VERSION 5.7 ;
BUSBITCHARS "[]" ;
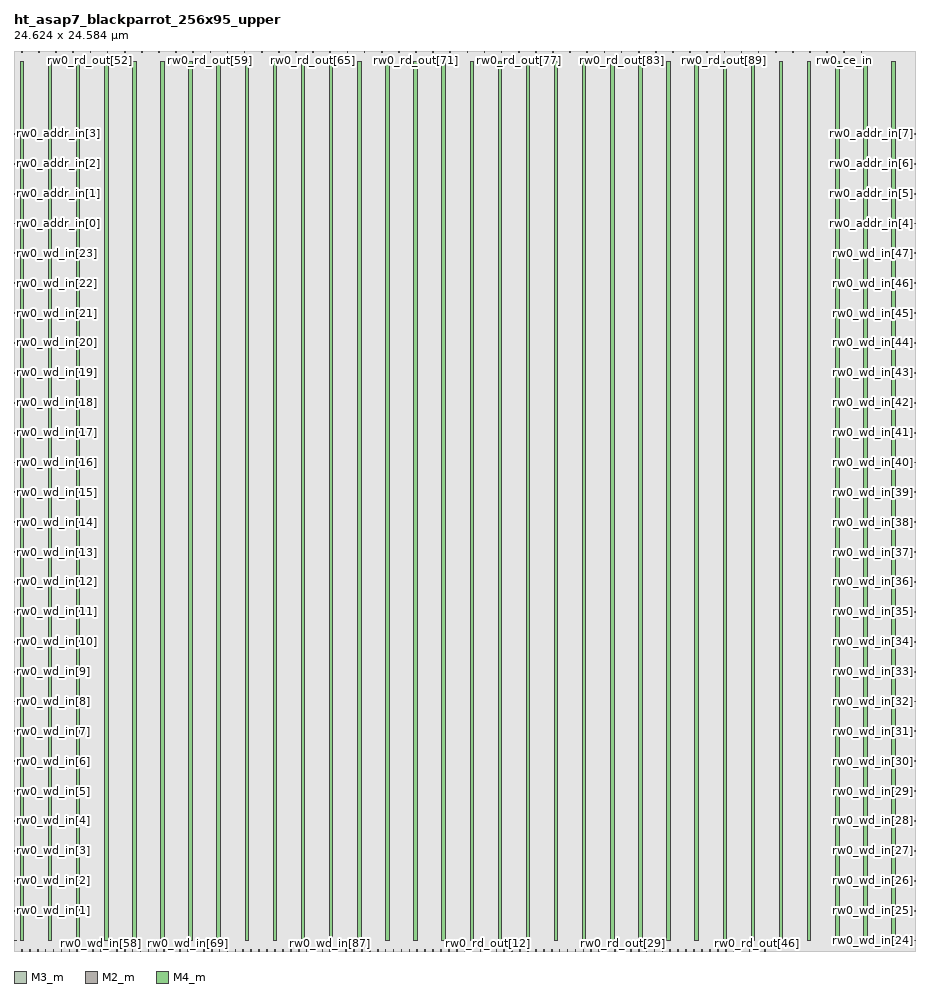
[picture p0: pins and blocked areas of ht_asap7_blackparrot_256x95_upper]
MACRO ht_asap7_blackparrot_256x95_upper
  FOREIGN ht_asap7_blackparrot_256x95_upper 0 0 ;
  SYMMETRY X Y R90 ;
  SIZE 24.624 BY 24.584 ;
  CLASS COVER ;
  PIN rw0_wd_in[0]
    DIRECTION INPUT ;
    USE SIGNAL ;
    SHAPE ABUTMENT ;
    PORT
      LAYER M3_m ;
      RECT 0.000 0.276 0.072 0.300 ;
    END
  END rw0_wd_in[0]
  PIN rw0_wd_in[1]
    DIRECTION INPUT ;
    USE SIGNAL ;
    SHAPE ABUTMENT ;
    PORT
      LAYER M3_m ;
      RECT 0.000 1.092 0.072 1.116 ;
    END
  END rw0_wd_in[1]
  PIN rw0_wd_in[2]
    DIRECTION INPUT ;
    USE SIGNAL ;
    SHAPE ABUTMENT ;
    PORT
      LAYER M3_m ;
      RECT 0.000 1.908 0.072 1.932 ;
    END
  END rw0_wd_in[2]
  PIN rw0_wd_in[3]
    DIRECTION INPUT ;
    USE SIGNAL ;
    SHAPE ABUTMENT ;
    PORT
      LAYER M3_m ;
      RECT 0.000 2.724 0.072 2.748 ;
    END
  END rw0_wd_in[3]
  PIN rw0_wd_in[4]
    DIRECTION INPUT ;
    USE SIGNAL ;
    SHAPE ABUTMENT ;
    PORT
      LAYER M3_m ;
      RECT 0.000 3.540 0.072 3.564 ;
    END
  END rw0_wd_in[4]
  PIN rw0_wd_in[5]
    DIRECTION INPUT ;
    USE SIGNAL ;
    SHAPE ABUTMENT ;
    PORT
      LAYER M3_m ;
      RECT 0.000 4.356 0.072 4.380 ;
    END
  END rw0_wd_in[5]
  PIN rw0_wd_in[6]
    DIRECTION INPUT ;
    USE SIGNAL ;
    SHAPE ABUTMENT ;
    PORT
      LAYER M3_m ;
      RECT 0.000 5.172 0.072 5.196 ;
    END
  END rw0_wd_in[6]
  PIN rw0_wd_in[7]
    DIRECTION INPUT ;
    USE SIGNAL ;
    SHAPE ABUTMENT ;
    PORT
      LAYER M3_m ;
      RECT 0.000 5.988 0.072 6.012 ;
    END
  END rw0_wd_in[7]
  PIN rw0_wd_in[8]
    DIRECTION INPUT ;
    USE SIGNAL ;
    SHAPE ABUTMENT ;
    PORT
      LAYER M3_m ;
      RECT 0.000 6.804 0.072 6.828 ;
    END
  END rw0_wd_in[8]
  PIN rw0_wd_in[9]
    DIRECTION INPUT ;
    USE SIGNAL ;
    SHAPE ABUTMENT ;
    PORT
      LAYER M3_m ;
      RECT 0.000 7.620 0.072 7.644 ;
    END
  END rw0_wd_in[9]
  PIN rw0_wd_in[10]
    DIRECTION INPUT ;
    USE SIGNAL ;
    SHAPE ABUTMENT ;
    PORT
      LAYER M3_m ;
      RECT 0.000 8.436 0.072 8.460 ;
    END
  END rw0_wd_in[10]
  PIN rw0_wd_in[11]
    DIRECTION INPUT ;
    USE SIGNAL ;
    SHAPE ABUTMENT ;
    PORT
      LAYER M3_m ;
      RECT 0.000 9.252 0.072 9.276 ;
    END
  END rw0_wd_in[11]
  PIN rw0_wd_in[12]
    DIRECTION INPUT ;
    USE SIGNAL ;
    SHAPE ABUTMENT ;
    PORT
      LAYER M3_m ;
      RECT 0.000 10.068 0.072 10.092 ;
    END
  END rw0_wd_in[12]
  PIN rw0_wd_in[13]
    DIRECTION INPUT ;
    USE SIGNAL ;
    SHAPE ABUTMENT ;
    PORT
      LAYER M3_m ;
      RECT 0.000 10.884 0.072 10.908 ;
    END
  END rw0_wd_in[13]
  PIN rw0_wd_in[14]
    DIRECTION INPUT ;
    USE SIGNAL ;
    SHAPE ABUTMENT ;
    PORT
      LAYER M3_m ;
      RECT 0.000 11.700 0.072 11.724 ;
    END
  END rw0_wd_in[14]
  PIN rw0_wd_in[15]
    DIRECTION INPUT ;
    USE SIGNAL ;
    SHAPE ABUTMENT ;
    PORT
      LAYER M3_m ;
      RECT 0.000 12.516 0.072 12.540 ;
    END
  END rw0_wd_in[15]
  PIN rw0_wd_in[16]
    DIRECTION INPUT ;
    USE SIGNAL ;
    SHAPE ABUTMENT ;
    PORT
      LAYER M3_m ;
      RECT 0.000 13.332 0.072 13.356 ;
    END
  END rw0_wd_in[16]
  PIN rw0_wd_in[17]
    DIRECTION INPUT ;
    USE SIGNAL ;
    SHAPE ABUTMENT ;
    PORT
      LAYER M3_m ;
      RECT 0.000 14.148 0.072 14.172 ;
    END
  END rw0_wd_in[17]
  PIN rw0_wd_in[18]
    DIRECTION INPUT ;
    USE SIGNAL ;
    SHAPE ABUTMENT ;
    PORT
      LAYER M3_m ;
      RECT 0.000 14.964 0.072 14.988 ;
    END
  END rw0_wd_in[18]
  PIN rw0_wd_in[19]
    DIRECTION INPUT ;
    USE SIGNAL ;
    SHAPE ABUTMENT ;
    PORT
      LAYER M3_m ;
      RECT 0.000 15.780 0.072 15.804 ;
    END
  END rw0_wd_in[19]
  PIN rw0_wd_in[20]
    DIRECTION INPUT ;
    USE SIGNAL ;
    SHAPE ABUTMENT ;
    PORT
      LAYER M3_m ;
      RECT 0.000 16.596 0.072 16.620 ;
    END
  END rw0_wd_in[20]
  PIN rw0_wd_in[21]
    DIRECTION INPUT ;
    USE SIGNAL ;
    SHAPE ABUTMENT ;
    PORT
      LAYER M3_m ;
      RECT 0.000 17.412 0.072 17.436 ;
    END
  END rw0_wd_in[21]
  PIN rw0_wd_in[22]
    DIRECTION INPUT ;
    USE SIGNAL ;
    SHAPE ABUTMENT ;
    PORT
      LAYER M3_m ;
      RECT 0.000 18.228 0.072 18.252 ;
    END
  END rw0_wd_in[22]
  PIN rw0_wd_in[23]
    DIRECTION INPUT ;
    USE SIGNAL ;
    SHAPE ABUTMENT ;
    PORT
      LAYER M3_m ;
      RECT 0.000 19.044 0.072 19.068 ;
    END
  END rw0_wd_in[23]
  PIN rw0_wd_in[24]
    DIRECTION INPUT ;
    USE SIGNAL ;
    SHAPE ABUTMENT ;
    PORT
      LAYER M3_m ;
      RECT 24.552 0.276 24.624 0.300 ;
    END
  END rw0_wd_in[24]
  PIN rw0_wd_in[25]
    DIRECTION INPUT ;
    USE SIGNAL ;
    SHAPE ABUTMENT ;
    PORT
      LAYER M3_m ;
      RECT 24.552 1.092 24.624 1.116 ;
    END
  END rw0_wd_in[25]
  PIN rw0_wd_in[26]
    DIRECTION INPUT ;
    USE SIGNAL ;
    SHAPE ABUTMENT ;
    PORT
      LAYER M3_m ;
      RECT 24.552 1.908 24.624 1.932 ;
    END
  END rw0_wd_in[26]
  PIN rw0_wd_in[27]
    DIRECTION INPUT ;
    USE SIGNAL ;
    SHAPE ABUTMENT ;
    PORT
      LAYER M3_m ;
      RECT 24.552 2.724 24.624 2.748 ;
    END
  END rw0_wd_in[27]
  PIN rw0_wd_in[28]
    DIRECTION INPUT ;
    USE SIGNAL ;
    SHAPE ABUTMENT ;
    PORT
      LAYER M3_m ;
      RECT 24.552 3.540 24.624 3.564 ;
    END
  END rw0_wd_in[28]
  PIN rw0_wd_in[29]
    DIRECTION INPUT ;
    USE SIGNAL ;
    SHAPE ABUTMENT ;
    PORT
      LAYER M3_m ;
      RECT 24.552 4.356 24.624 4.380 ;
    END
  END rw0_wd_in[29]
  PIN rw0_wd_in[30]
    DIRECTION INPUT ;
    USE SIGNAL ;
    SHAPE ABUTMENT ;
    PORT
      LAYER M3_m ;
      RECT 24.552 5.172 24.624 5.196 ;
    END
  END rw0_wd_in[30]
  PIN rw0_wd_in[31]
    DIRECTION INPUT ;
    USE SIGNAL ;
    SHAPE ABUTMENT ;
    PORT
      LAYER M3_m ;
      RECT 24.552 5.988 24.624 6.012 ;
    END
  END rw0_wd_in[31]
  PIN rw0_wd_in[32]
    DIRECTION INPUT ;
    USE SIGNAL ;
    SHAPE ABUTMENT ;
    PORT
      LAYER M3_m ;
      RECT 24.552 6.804 24.624 6.828 ;
    END
  END rw0_wd_in[32]
  PIN rw0_wd_in[33]
    DIRECTION INPUT ;
    USE SIGNAL ;
    SHAPE ABUTMENT ;
    PORT
      LAYER M3_m ;
      RECT 24.552 7.620 24.624 7.644 ;
    END
  END rw0_wd_in[33]
  PIN rw0_wd_in[34]
    DIRECTION INPUT ;
    USE SIGNAL ;
    SHAPE ABUTMENT ;
    PORT
      LAYER M3_m ;
      RECT 24.552 8.436 24.624 8.460 ;
    END
  END rw0_wd_in[34]
  PIN rw0_wd_in[35]
    DIRECTION INPUT ;
    USE SIGNAL ;
    SHAPE ABUTMENT ;
    PORT
      LAYER M3_m ;
      RECT 24.552 9.252 24.624 9.276 ;
    END
  END rw0_wd_in[35]
  PIN rw0_wd_in[36]
    DIRECTION INPUT ;
    USE SIGNAL ;
    SHAPE ABUTMENT ;
    PORT
      LAYER M3_m ;
      RECT 24.552 10.068 24.624 10.092 ;
    END
  END rw0_wd_in[36]
  PIN rw0_wd_in[37]
    DIRECTION INPUT ;
    USE SIGNAL ;
    SHAPE ABUTMENT ;
    PORT
      LAYER M3_m ;
      RECT 24.552 10.884 24.624 10.908 ;
    END
  END rw0_wd_in[37]
  PIN rw0_wd_in[38]
    DIRECTION INPUT ;
    USE SIGNAL ;
    SHAPE ABUTMENT ;
    PORT
      LAYER M3_m ;
      RECT 24.552 11.700 24.624 11.724 ;
    END
  END rw0_wd_in[38]
  PIN rw0_wd_in[39]
    DIRECTION INPUT ;
    USE SIGNAL ;
    SHAPE ABUTMENT ;
    PORT
      LAYER M3_m ;
      RECT 24.552 12.516 24.624 12.540 ;
    END
  END rw0_wd_in[39]
  PIN rw0_wd_in[40]
    DIRECTION INPUT ;
    USE SIGNAL ;
    SHAPE ABUTMENT ;
    PORT
      LAYER M3_m ;
      RECT 24.552 13.332 24.624 13.356 ;
    END
  END rw0_wd_in[40]
  PIN rw0_wd_in[41]
    DIRECTION INPUT ;
    USE SIGNAL ;
    SHAPE ABUTMENT ;
    PORT
      LAYER M3_m ;
      RECT 24.552 14.148 24.624 14.172 ;
    END
  END rw0_wd_in[41]
  PIN rw0_wd_in[42]
    DIRECTION INPUT ;
    USE SIGNAL ;
    SHAPE ABUTMENT ;
    PORT
      LAYER M3_m ;
      RECT 24.552 14.964 24.624 14.988 ;
    END
  END rw0_wd_in[42]
  PIN rw0_wd_in[43]
    DIRECTION INPUT ;
    USE SIGNAL ;
    SHAPE ABUTMENT ;
    PORT
      LAYER M3_m ;
      RECT 24.552 15.780 24.624 15.804 ;
    END
  END rw0_wd_in[43]
  PIN rw0_wd_in[44]
    DIRECTION INPUT ;
    USE SIGNAL ;
    SHAPE ABUTMENT ;
    PORT
      LAYER M3_m ;
      RECT 24.552 16.596 24.624 16.620 ;
    END
  END rw0_wd_in[44]
  PIN rw0_wd_in[45]
    DIRECTION INPUT ;
    USE SIGNAL ;
    SHAPE ABUTMENT ;
    PORT
      LAYER M3_m ;
      RECT 24.552 17.412 24.624 17.436 ;
    END
  END rw0_wd_in[45]
  PIN rw0_wd_in[46]
    DIRECTION INPUT ;
    USE SIGNAL ;
    SHAPE ABUTMENT ;
    PORT
      LAYER M3_m ;
      RECT 24.552 18.228 24.624 18.252 ;
    END
  END rw0_wd_in[46]
  PIN rw0_wd_in[47]
    DIRECTION INPUT ;
    USE SIGNAL ;
    SHAPE ABUTMENT ;
    PORT
      LAYER M3_m ;
      RECT 24.552 19.044 24.624 19.068 ;
    END
  END rw0_wd_in[47]
  PIN rw0_wd_in[48]
    DIRECTION INPUT ;
    USE SIGNAL ;
    SHAPE ABUTMENT ;
    PORT
      LAYER M2_m ;
      RECT 0.207 0.000 0.225 0.054 ;
    END
  END rw0_wd_in[48]
  PIN rw0_wd_in[49]
    DIRECTION INPUT ;
    USE SIGNAL ;
    SHAPE ABUTMENT ;
    PORT
      LAYER M2_m ;
      RECT 0.423 0.000 0.441 0.054 ;
    END
  END rw0_wd_in[49]
  PIN rw0_wd_in[50]
    DIRECTION INPUT ;
    USE SIGNAL ;
    SHAPE ABUTMENT ;
    PORT
      LAYER M2_m ;
      RECT 0.639 0.000 0.657 0.054 ;
    END
  END rw0_wd_in[50]
  PIN rw0_wd_in[51]
    DIRECTION INPUT ;
    USE SIGNAL ;
    SHAPE ABUTMENT ;
    PORT
      LAYER M2_m ;
      RECT 0.855 0.000 0.873 0.054 ;
    END
  END rw0_wd_in[51]
  PIN rw0_wd_in[52]
    DIRECTION INPUT ;
    USE SIGNAL ;
    SHAPE ABUTMENT ;
    PORT
      LAYER M2_m ;
      RECT 1.071 0.000 1.089 0.054 ;
    END
  END rw0_wd_in[52]
  PIN rw0_wd_in[53]
    DIRECTION INPUT ;
    USE SIGNAL ;
    SHAPE ABUTMENT ;
    PORT
      LAYER M2_m ;
      RECT 1.287 0.000 1.305 0.054 ;
    END
  END rw0_wd_in[53]
  PIN rw0_wd_in[54]
    DIRECTION INPUT ;
    USE SIGNAL ;
    SHAPE ABUTMENT ;
    PORT
      LAYER M2_m ;
      RECT 1.503 0.000 1.521 0.054 ;
    END
  END rw0_wd_in[54]
  PIN rw0_wd_in[55]
    DIRECTION INPUT ;
    USE SIGNAL ;
    SHAPE ABUTMENT ;
    PORT
      LAYER M2_m ;
      RECT 1.719 0.000 1.737 0.054 ;
    END
  END rw0_wd_in[55]
  PIN rw0_wd_in[56]
    DIRECTION INPUT ;
    USE SIGNAL ;
    SHAPE ABUTMENT ;
    PORT
      LAYER M2_m ;
      RECT 1.935 0.000 1.953 0.054 ;
    END
  END rw0_wd_in[56]
  PIN rw0_wd_in[57]
    DIRECTION INPUT ;
    USE SIGNAL ;
    SHAPE ABUTMENT ;
    PORT
      LAYER M2_m ;
      RECT 2.151 0.000 2.169 0.054 ;
    END
  END rw0_wd_in[57]
  PIN rw0_wd_in[58]
    DIRECTION INPUT ;
    USE SIGNAL ;
    SHAPE ABUTMENT ;
    PORT
      LAYER M2_m ;
      RECT 2.367 0.000 2.385 0.054 ;
    END
  END rw0_wd_in[58]
  PIN rw0_wd_in[59]
    DIRECTION INPUT ;
    USE SIGNAL ;
    SHAPE ABUTMENT ;
    PORT
      LAYER M2_m ;
      RECT 2.583 0.000 2.601 0.054 ;
    END
  END rw0_wd_in[59]
  PIN rw0_wd_in[60]
    DIRECTION INPUT ;
    USE SIGNAL ;
    SHAPE ABUTMENT ;
    PORT
      LAYER M2_m ;
      RECT 2.799 0.000 2.817 0.054 ;
    END
  END rw0_wd_in[60]
  PIN rw0_wd_in[61]
    DIRECTION INPUT ;
    USE SIGNAL ;
    SHAPE ABUTMENT ;
    PORT
      LAYER M2_m ;
      RECT 3.015 0.000 3.033 0.054 ;
    END
  END rw0_wd_in[61]
  PIN rw0_wd_in[62]
    DIRECTION INPUT ;
    USE SIGNAL ;
    SHAPE ABUTMENT ;
    PORT
      LAYER M2_m ;
      RECT 3.231 0.000 3.249 0.054 ;
    END
  END rw0_wd_in[62]
  PIN rw0_wd_in[63]
    DIRECTION INPUT ;
    USE SIGNAL ;
    SHAPE ABUTMENT ;
    PORT
      LAYER M2_m ;
      RECT 3.447 0.000 3.465 0.054 ;
    END
  END rw0_wd_in[63]
  PIN rw0_wd_in[64]
    DIRECTION INPUT ;
    USE SIGNAL ;
    SHAPE ABUTMENT ;
    PORT
      LAYER M2_m ;
      RECT 3.663 0.000 3.681 0.054 ;
    END
  END rw0_wd_in[64]
  PIN rw0_wd_in[65]
    DIRECTION INPUT ;
    USE SIGNAL ;
    SHAPE ABUTMENT ;
    PORT
      LAYER M2_m ;
      RECT 3.879 0.000 3.897 0.054 ;
    END
  END rw0_wd_in[65]
  PIN rw0_wd_in[66]
    DIRECTION INPUT ;
    USE SIGNAL ;
    SHAPE ABUTMENT ;
    PORT
      LAYER M2_m ;
      RECT 4.095 0.000 4.113 0.054 ;
    END
  END rw0_wd_in[66]
  PIN rw0_wd_in[67]
    DIRECTION INPUT ;
    USE SIGNAL ;
    SHAPE ABUTMENT ;
    PORT
      LAYER M2_m ;
      RECT 4.311 0.000 4.329 0.054 ;
    END
  END rw0_wd_in[67]
  PIN rw0_wd_in[68]
    DIRECTION INPUT ;
    USE SIGNAL ;
    SHAPE ABUTMENT ;
    PORT
      LAYER M2_m ;
      RECT 4.527 0.000 4.545 0.054 ;
    END
  END rw0_wd_in[68]
  PIN rw0_wd_in[69]
    DIRECTION INPUT ;
    USE SIGNAL ;
    SHAPE ABUTMENT ;
    PORT
      LAYER M2_m ;
      RECT 4.743 0.000 4.761 0.054 ;
    END
  END rw0_wd_in[69]
  PIN rw0_wd_in[70]
    DIRECTION INPUT ;
    USE SIGNAL ;
    SHAPE ABUTMENT ;
    PORT
      LAYER M2_m ;
      RECT 4.959 0.000 4.977 0.054 ;
    END
  END rw0_wd_in[70]
  PIN rw0_wd_in[71]
    DIRECTION INPUT ;
    USE SIGNAL ;
    SHAPE ABUTMENT ;
    PORT
      LAYER M2_m ;
      RECT 5.175 0.000 5.193 0.054 ;
    END
  END rw0_wd_in[71]
  PIN rw0_wd_in[72]
    DIRECTION INPUT ;
    USE SIGNAL ;
    SHAPE ABUTMENT ;
    PORT
      LAYER M2_m ;
      RECT 5.391 0.000 5.409 0.054 ;
    END
  END rw0_wd_in[72]
  PIN rw0_wd_in[73]
    DIRECTION INPUT ;
    USE SIGNAL ;
    SHAPE ABUTMENT ;
    PORT
      LAYER M2_m ;
      RECT 5.607 0.000 5.625 0.054 ;
    END
  END rw0_wd_in[73]
  PIN rw0_wd_in[74]
    DIRECTION INPUT ;
    USE SIGNAL ;
    SHAPE ABUTMENT ;
    PORT
      LAYER M2_m ;
      RECT 5.823 0.000 5.841 0.054 ;
    END
  END rw0_wd_in[74]
  PIN rw0_wd_in[75]
    DIRECTION INPUT ;
    USE SIGNAL ;
    SHAPE ABUTMENT ;
    PORT
      LAYER M2_m ;
      RECT 6.039 0.000 6.057 0.054 ;
    END
  END rw0_wd_in[75]
  PIN rw0_wd_in[76]
    DIRECTION INPUT ;
    USE SIGNAL ;
    SHAPE ABUTMENT ;
    PORT
      LAYER M2_m ;
      RECT 6.255 0.000 6.273 0.054 ;
    END
  END rw0_wd_in[76]
  PIN rw0_wd_in[77]
    DIRECTION INPUT ;
    USE SIGNAL ;
    SHAPE ABUTMENT ;
    PORT
      LAYER M2_m ;
      RECT 6.471 0.000 6.489 0.054 ;
    END
  END rw0_wd_in[77]
  PIN rw0_wd_in[78]
    DIRECTION INPUT ;
    USE SIGNAL ;
    SHAPE ABUTMENT ;
    PORT
      LAYER M2_m ;
      RECT 6.687 0.000 6.705 0.054 ;
    END
  END rw0_wd_in[78]
  PIN rw0_wd_in[79]
    DIRECTION INPUT ;
    USE SIGNAL ;
    SHAPE ABUTMENT ;
    PORT
      LAYER M2_m ;
      RECT 6.903 0.000 6.921 0.054 ;
    END
  END rw0_wd_in[79]
  PIN rw0_wd_in[80]
    DIRECTION INPUT ;
    USE SIGNAL ;
    SHAPE ABUTMENT ;
    PORT
      LAYER M2_m ;
      RECT 7.119 0.000 7.137 0.054 ;
    END
  END rw0_wd_in[80]
  PIN rw0_wd_in[81]
    DIRECTION INPUT ;
    USE SIGNAL ;
    SHAPE ABUTMENT ;
    PORT
      LAYER M2_m ;
      RECT 7.335 0.000 7.353 0.054 ;
    END
  END rw0_wd_in[81]
  PIN rw0_wd_in[82]
    DIRECTION INPUT ;
    USE SIGNAL ;
    SHAPE ABUTMENT ;
    PORT
      LAYER M2_m ;
      RECT 7.551 0.000 7.569 0.054 ;
    END
  END rw0_wd_in[82]
  PIN rw0_wd_in[83]
    DIRECTION INPUT ;
    USE SIGNAL ;
    SHAPE ABUTMENT ;
    PORT
      LAYER M2_m ;
      RECT 7.767 0.000 7.785 0.054 ;
    END
  END rw0_wd_in[83]
  PIN rw0_wd_in[84]
    DIRECTION INPUT ;
    USE SIGNAL ;
    SHAPE ABUTMENT ;
    PORT
      LAYER M2_m ;
      RECT 7.983 0.000 8.001 0.054 ;
    END
  END rw0_wd_in[84]
  PIN rw0_wd_in[85]
    DIRECTION INPUT ;
    USE SIGNAL ;
    SHAPE ABUTMENT ;
    PORT
      LAYER M2_m ;
      RECT 8.199 0.000 8.217 0.054 ;
    END
  END rw0_wd_in[85]
  PIN rw0_wd_in[86]
    DIRECTION INPUT ;
    USE SIGNAL ;
    SHAPE ABUTMENT ;
    PORT
      LAYER M2_m ;
      RECT 8.415 0.000 8.433 0.054 ;
    END
  END rw0_wd_in[86]
  PIN rw0_wd_in[87]
    DIRECTION INPUT ;
    USE SIGNAL ;
    SHAPE ABUTMENT ;
    PORT
      LAYER M2_m ;
      RECT 8.631 0.000 8.649 0.054 ;
    END
  END rw0_wd_in[87]
  PIN rw0_wd_in[88]
    DIRECTION INPUT ;
    USE SIGNAL ;
    SHAPE ABUTMENT ;
    PORT
      LAYER M2_m ;
      RECT 8.847 0.000 8.865 0.054 ;
    END
  END rw0_wd_in[88]
  PIN rw0_wd_in[89]
    DIRECTION INPUT ;
    USE SIGNAL ;
    SHAPE ABUTMENT ;
    PORT
      LAYER M2_m ;
      RECT 9.063 0.000 9.081 0.054 ;
    END
  END rw0_wd_in[89]
  PIN rw0_wd_in[90]
    DIRECTION INPUT ;
    USE SIGNAL ;
    SHAPE ABUTMENT ;
    PORT
      LAYER M2_m ;
      RECT 9.279 0.000 9.297 0.054 ;
    END
  END rw0_wd_in[90]
  PIN rw0_wd_in[91]
    DIRECTION INPUT ;
    USE SIGNAL ;
    SHAPE ABUTMENT ;
    PORT
      LAYER M2_m ;
      RECT 9.495 0.000 9.513 0.054 ;
    END
  END rw0_wd_in[91]
  PIN rw0_wd_in[92]
    DIRECTION INPUT ;
    USE SIGNAL ;
    SHAPE ABUTMENT ;
    PORT
      LAYER M2_m ;
      RECT 9.711 0.000 9.729 0.054 ;
    END
  END rw0_wd_in[92]
  PIN rw0_wd_in[93]
    DIRECTION INPUT ;
    USE SIGNAL ;
    SHAPE ABUTMENT ;
    PORT
      LAYER M2_m ;
      RECT 9.927 0.000 9.945 0.054 ;
    END
  END rw0_wd_in[93]
  PIN rw0_wd_in[94]
    DIRECTION INPUT ;
    USE SIGNAL ;
    SHAPE ABUTMENT ;
    PORT
      LAYER M2_m ;
      RECT 10.143 0.000 10.161 0.054 ;
    END
  END rw0_wd_in[94]
  PIN rw0_rd_out[0]
    DIRECTION OUTPUT ;
    USE SIGNAL ;
    SHAPE ABUTMENT ;
    PORT
      LAYER M2_m ;
      RECT 10.359 0.000 10.377 0.054 ;
    END
  END rw0_rd_out[0]
  PIN rw0_rd_out[1]
    DIRECTION OUTPUT ;
    USE SIGNAL ;
    SHAPE ABUTMENT ;
    PORT
      LAYER M2_m ;
      RECT 10.575 0.000 10.593 0.054 ;
    END
  END rw0_rd_out[1]
  PIN rw0_rd_out[2]
    DIRECTION OUTPUT ;
    USE SIGNAL ;
    SHAPE ABUTMENT ;
    PORT
      LAYER M2_m ;
      RECT 10.791 0.000 10.809 0.054 ;
    END
  END rw0_rd_out[2]
  PIN rw0_rd_out[3]
    DIRECTION OUTPUT ;
    USE SIGNAL ;
    SHAPE ABUTMENT ;
    PORT
      LAYER M2_m ;
      RECT 11.007 0.000 11.025 0.054 ;
    END
  END rw0_rd_out[3]
  PIN rw0_rd_out[4]
    DIRECTION OUTPUT ;
    USE SIGNAL ;
    SHAPE ABUTMENT ;
    PORT
      LAYER M2_m ;
      RECT 11.223 0.000 11.241 0.054 ;
    END
  END rw0_rd_out[4]
  PIN rw0_rd_out[5]
    DIRECTION OUTPUT ;
    USE SIGNAL ;
    SHAPE ABUTMENT ;
    PORT
      LAYER M2_m ;
      RECT 11.439 0.000 11.457 0.054 ;
    END
  END rw0_rd_out[5]
  PIN rw0_rd_out[6]
    DIRECTION OUTPUT ;
    USE SIGNAL ;
    SHAPE ABUTMENT ;
    PORT
      LAYER M2_m ;
      RECT 11.655 0.000 11.673 0.054 ;
    END
  END rw0_rd_out[6]
  PIN rw0_rd_out[7]
    DIRECTION OUTPUT ;
    USE SIGNAL ;
    SHAPE ABUTMENT ;
    PORT
      LAYER M2_m ;
      RECT 11.871 0.000 11.889 0.054 ;
    END
  END rw0_rd_out[7]
  PIN rw0_rd_out[8]
    DIRECTION OUTPUT ;
    USE SIGNAL ;
    SHAPE ABUTMENT ;
    PORT
      LAYER M2_m ;
      RECT 12.087 0.000 12.105 0.054 ;
    END
  END rw0_rd_out[8]
  PIN rw0_rd_out[9]
    DIRECTION OUTPUT ;
    USE SIGNAL ;
    SHAPE ABUTMENT ;
    PORT
      LAYER M2_m ;
      RECT 12.303 0.000 12.321 0.054 ;
    END
  END rw0_rd_out[9]
  PIN rw0_rd_out[10]
    DIRECTION OUTPUT ;
    USE SIGNAL ;
    SHAPE ABUTMENT ;
    PORT
      LAYER M2_m ;
      RECT 12.519 0.000 12.537 0.054 ;
    END
  END rw0_rd_out[10]
  PIN rw0_rd_out[11]
    DIRECTION OUTPUT ;
    USE SIGNAL ;
    SHAPE ABUTMENT ;
    PORT
      LAYER M2_m ;
      RECT 12.735 0.000 12.753 0.054 ;
    END
  END rw0_rd_out[11]
  PIN rw0_rd_out[12]
    DIRECTION OUTPUT ;
    USE SIGNAL ;
    SHAPE ABUTMENT ;
    PORT
      LAYER M2_m ;
      RECT 12.951 0.000 12.969 0.054 ;
    END
  END rw0_rd_out[12]
  PIN rw0_rd_out[13]
    DIRECTION OUTPUT ;
    USE SIGNAL ;
    SHAPE ABUTMENT ;
    PORT
      LAYER M2_m ;
      RECT 13.167 0.000 13.185 0.054 ;
    END
  END rw0_rd_out[13]
  PIN rw0_rd_out[14]
    DIRECTION OUTPUT ;
    USE SIGNAL ;
    SHAPE ABUTMENT ;
    PORT
      LAYER M2_m ;
      RECT 13.383 0.000 13.401 0.054 ;
    END
  END rw0_rd_out[14]
  PIN rw0_rd_out[15]
    DIRECTION OUTPUT ;
    USE SIGNAL ;
    SHAPE ABUTMENT ;
    PORT
      LAYER M2_m ;
      RECT 13.599 0.000 13.617 0.054 ;
    END
  END rw0_rd_out[15]
  PIN rw0_rd_out[16]
    DIRECTION OUTPUT ;
    USE SIGNAL ;
    SHAPE ABUTMENT ;
    PORT
      LAYER M2_m ;
      RECT 13.815 0.000 13.833 0.054 ;
    END
  END rw0_rd_out[16]
  PIN rw0_rd_out[17]
    DIRECTION OUTPUT ;
    USE SIGNAL ;
    SHAPE ABUTMENT ;
    PORT
      LAYER M2_m ;
      RECT 14.031 0.000 14.049 0.054 ;
    END
  END rw0_rd_out[17]
  PIN rw0_rd_out[18]
    DIRECTION OUTPUT ;
    USE SIGNAL ;
    SHAPE ABUTMENT ;
    PORT
      LAYER M2_m ;
      RECT 14.247 0.000 14.265 0.054 ;
    END
  END rw0_rd_out[18]
  PIN rw0_rd_out[19]
    DIRECTION OUTPUT ;
    USE SIGNAL ;
    SHAPE ABUTMENT ;
    PORT
      LAYER M2_m ;
      RECT 14.463 0.000 14.481 0.054 ;
    END
  END rw0_rd_out[19]
  PIN rw0_rd_out[20]
    DIRECTION OUTPUT ;
    USE SIGNAL ;
    SHAPE ABUTMENT ;
    PORT
      LAYER M2_m ;
      RECT 14.679 0.000 14.697 0.054 ;
    END
  END rw0_rd_out[20]
  PIN rw0_rd_out[21]
    DIRECTION OUTPUT ;
    USE SIGNAL ;
    SHAPE ABUTMENT ;
    PORT
      LAYER M2_m ;
      RECT 14.895 0.000 14.913 0.054 ;
    END
  END rw0_rd_out[21]
  PIN rw0_rd_out[22]
    DIRECTION OUTPUT ;
    USE SIGNAL ;
    SHAPE ABUTMENT ;
    PORT
      LAYER M2_m ;
      RECT 15.111 0.000 15.129 0.054 ;
    END
  END rw0_rd_out[22]
  PIN rw0_rd_out[23]
    DIRECTION OUTPUT ;
    USE SIGNAL ;
    SHAPE ABUTMENT ;
    PORT
      LAYER M2_m ;
      RECT 15.327 0.000 15.345 0.054 ;
    END
  END rw0_rd_out[23]
  PIN rw0_rd_out[24]
    DIRECTION OUTPUT ;
    USE SIGNAL ;
    SHAPE ABUTMENT ;
    PORT
      LAYER M2_m ;
      RECT 15.543 0.000 15.561 0.054 ;
    END
  END rw0_rd_out[24]
  PIN rw0_rd_out[25]
    DIRECTION OUTPUT ;
    USE SIGNAL ;
    SHAPE ABUTMENT ;
    PORT
      LAYER M2_m ;
      RECT 15.759 0.000 15.777 0.054 ;
    END
  END rw0_rd_out[25]
  PIN rw0_rd_out[26]
    DIRECTION OUTPUT ;
    USE SIGNAL ;
    SHAPE ABUTMENT ;
    PORT
      LAYER M2_m ;
      RECT 15.975 0.000 15.993 0.054 ;
    END
  END rw0_rd_out[26]
  PIN rw0_rd_out[27]
    DIRECTION OUTPUT ;
    USE SIGNAL ;
    SHAPE ABUTMENT ;
    PORT
      LAYER M2_m ;
      RECT 16.191 0.000 16.209 0.054 ;
    END
  END rw0_rd_out[27]
  PIN rw0_rd_out[28]
    DIRECTION OUTPUT ;
    USE SIGNAL ;
    SHAPE ABUTMENT ;
    PORT
      LAYER M2_m ;
      RECT 16.407 0.000 16.425 0.054 ;
    END
  END rw0_rd_out[28]
  PIN rw0_rd_out[29]
    DIRECTION OUTPUT ;
    USE SIGNAL ;
    SHAPE ABUTMENT ;
    PORT
      LAYER M2_m ;
      RECT 16.623 0.000 16.641 0.054 ;
    END
  END rw0_rd_out[29]
  PIN rw0_rd_out[30]
    DIRECTION OUTPUT ;
    USE SIGNAL ;
    SHAPE ABUTMENT ;
    PORT
      LAYER M2_m ;
      RECT 16.839 0.000 16.857 0.054 ;
    END
  END rw0_rd_out[30]
  PIN rw0_rd_out[31]
    DIRECTION OUTPUT ;
    USE SIGNAL ;
    SHAPE ABUTMENT ;
    PORT
      LAYER M2_m ;
      RECT 17.055 0.000 17.073 0.054 ;
    END
  END rw0_rd_out[31]
  PIN rw0_rd_out[32]
    DIRECTION OUTPUT ;
    USE SIGNAL ;
    SHAPE ABUTMENT ;
    PORT
      LAYER M2_m ;
      RECT 17.271 0.000 17.289 0.054 ;
    END
  END rw0_rd_out[32]
  PIN rw0_rd_out[33]
    DIRECTION OUTPUT ;
    USE SIGNAL ;
    SHAPE ABUTMENT ;
    PORT
      LAYER M2_m ;
      RECT 17.487 0.000 17.505 0.054 ;
    END
  END rw0_rd_out[33]
  PIN rw0_rd_out[34]
    DIRECTION OUTPUT ;
    USE SIGNAL ;
    SHAPE ABUTMENT ;
    PORT
      LAYER M2_m ;
      RECT 17.703 0.000 17.721 0.054 ;
    END
  END rw0_rd_out[34]
  PIN rw0_rd_out[35]
    DIRECTION OUTPUT ;
    USE SIGNAL ;
    SHAPE ABUTMENT ;
    PORT
      LAYER M2_m ;
      RECT 17.919 0.000 17.937 0.054 ;
    END
  END rw0_rd_out[35]
  PIN rw0_rd_out[36]
    DIRECTION OUTPUT ;
    USE SIGNAL ;
    SHAPE ABUTMENT ;
    PORT
      LAYER M2_m ;
      RECT 18.135 0.000 18.153 0.054 ;
    END
  END rw0_rd_out[36]
  PIN rw0_rd_out[37]
    DIRECTION OUTPUT ;
    USE SIGNAL ;
    SHAPE ABUTMENT ;
    PORT
      LAYER M2_m ;
      RECT 18.351 0.000 18.369 0.054 ;
    END
  END rw0_rd_out[37]
  PIN rw0_rd_out[38]
    DIRECTION OUTPUT ;
    USE SIGNAL ;
    SHAPE ABUTMENT ;
    PORT
      LAYER M2_m ;
      RECT 18.567 0.000 18.585 0.054 ;
    END
  END rw0_rd_out[38]
  PIN rw0_rd_out[39]
    DIRECTION OUTPUT ;
    USE SIGNAL ;
    SHAPE ABUTMENT ;
    PORT
      LAYER M2_m ;
      RECT 18.783 0.000 18.801 0.054 ;
    END
  END rw0_rd_out[39]
  PIN rw0_rd_out[40]
    DIRECTION OUTPUT ;
    USE SIGNAL ;
    SHAPE ABUTMENT ;
    PORT
      LAYER M2_m ;
      RECT 18.999 0.000 19.017 0.054 ;
    END
  END rw0_rd_out[40]
  PIN rw0_rd_out[41]
    DIRECTION OUTPUT ;
    USE SIGNAL ;
    SHAPE ABUTMENT ;
    PORT
      LAYER M2_m ;
      RECT 19.215 0.000 19.233 0.054 ;
    END
  END rw0_rd_out[41]
  PIN rw0_rd_out[42]
    DIRECTION OUTPUT ;
    USE SIGNAL ;
    SHAPE ABUTMENT ;
    PORT
      LAYER M2_m ;
      RECT 19.431 0.000 19.449 0.054 ;
    END
  END rw0_rd_out[42]
  PIN rw0_rd_out[43]
    DIRECTION OUTPUT ;
    USE SIGNAL ;
    SHAPE ABUTMENT ;
    PORT
      LAYER M2_m ;
      RECT 19.647 0.000 19.665 0.054 ;
    END
  END rw0_rd_out[43]
  PIN rw0_rd_out[44]
    DIRECTION OUTPUT ;
    USE SIGNAL ;
    SHAPE ABUTMENT ;
    PORT
      LAYER M2_m ;
      RECT 19.863 0.000 19.881 0.054 ;
    END
  END rw0_rd_out[44]
  PIN rw0_rd_out[45]
    DIRECTION OUTPUT ;
    USE SIGNAL ;
    SHAPE ABUTMENT ;
    PORT
      LAYER M2_m ;
      RECT 20.079 0.000 20.097 0.054 ;
    END
  END rw0_rd_out[45]
  PIN rw0_rd_out[46]
    DIRECTION OUTPUT ;
    USE SIGNAL ;
    SHAPE ABUTMENT ;
    PORT
      LAYER M2_m ;
      RECT 20.295 0.000 20.313 0.054 ;
    END
  END rw0_rd_out[46]
  PIN rw0_rd_out[47]
    DIRECTION OUTPUT ;
    USE SIGNAL ;
    SHAPE ABUTMENT ;
    PORT
      LAYER M2_m ;
      RECT 20.511 0.000 20.529 0.054 ;
    END
  END rw0_rd_out[47]
  PIN rw0_rd_out[48]
    DIRECTION OUTPUT ;
    USE SIGNAL ;
    SHAPE ABUTMENT ;
    PORT
      LAYER M2_m ;
      RECT 0.207 24.530 0.225 24.584 ;
    END
  END rw0_rd_out[48]
  PIN rw0_rd_out[49]
    DIRECTION OUTPUT ;
    USE SIGNAL ;
    SHAPE ABUTMENT ;
    PORT
      LAYER M2_m ;
      RECT 0.675 24.530 0.693 24.584 ;
    END
  END rw0_rd_out[49]
  PIN rw0_rd_out[50]
    DIRECTION OUTPUT ;
    USE SIGNAL ;
    SHAPE ABUTMENT ;
    PORT
      LAYER M2_m ;
      RECT 1.143 24.530 1.161 24.584 ;
    END
  END rw0_rd_out[50]
  PIN rw0_rd_out[51]
    DIRECTION OUTPUT ;
    USE SIGNAL ;
    SHAPE ABUTMENT ;
    PORT
      LAYER M2_m ;
      RECT 1.611 24.530 1.629 24.584 ;
    END
  END rw0_rd_out[51]
  PIN rw0_rd_out[52]
    DIRECTION OUTPUT ;
    USE SIGNAL ;
    SHAPE ABUTMENT ;
    PORT
      LAYER M2_m ;
      RECT 2.079 24.530 2.097 24.584 ;
    END
  END rw0_rd_out[52]
  PIN rw0_rd_out[53]
    DIRECTION OUTPUT ;
    USE SIGNAL ;
    SHAPE ABUTMENT ;
    PORT
      LAYER M2_m ;
      RECT 2.547 24.530 2.565 24.584 ;
    END
  END rw0_rd_out[53]
  PIN rw0_rd_out[54]
    DIRECTION OUTPUT ;
    USE SIGNAL ;
    SHAPE ABUTMENT ;
    PORT
      LAYER M2_m ;
      RECT 3.015 24.530 3.033 24.584 ;
    END
  END rw0_rd_out[54]
  PIN rw0_rd_out[55]
    DIRECTION OUTPUT ;
    USE SIGNAL ;
    SHAPE ABUTMENT ;
    PORT
      LAYER M2_m ;
      RECT 3.483 24.530 3.501 24.584 ;
    END
  END rw0_rd_out[55]
  PIN rw0_rd_out[56]
    DIRECTION OUTPUT ;
    USE SIGNAL ;
    SHAPE ABUTMENT ;
    PORT
      LAYER M2_m ;
      RECT 3.951 24.530 3.969 24.584 ;
    END
  END rw0_rd_out[56]
  PIN rw0_rd_out[57]
    DIRECTION OUTPUT ;
    USE SIGNAL ;
    SHAPE ABUTMENT ;
    PORT
      LAYER M2_m ;
      RECT 4.419 24.530 4.437 24.584 ;
    END
  END rw0_rd_out[57]
  PIN rw0_rd_out[58]
    DIRECTION OUTPUT ;
    USE SIGNAL ;
    SHAPE ABUTMENT ;
    PORT
      LAYER M2_m ;
      RECT 4.887 24.530 4.905 24.584 ;
    END
  END rw0_rd_out[58]
  PIN rw0_rd_out[59]
    DIRECTION OUTPUT ;
    USE SIGNAL ;
    SHAPE ABUTMENT ;
    PORT
      LAYER M2_m ;
      RECT 5.355 24.530 5.373 24.584 ;
    END
  END rw0_rd_out[59]
  PIN rw0_rd_out[60]
    DIRECTION OUTPUT ;
    USE SIGNAL ;
    SHAPE ABUTMENT ;
    PORT
      LAYER M2_m ;
      RECT 5.823 24.530 5.841 24.584 ;
    END
  END rw0_rd_out[60]
  PIN rw0_rd_out[61]
    DIRECTION OUTPUT ;
    USE SIGNAL ;
    SHAPE ABUTMENT ;
    PORT
      LAYER M2_m ;
      RECT 6.291 24.530 6.309 24.584 ;
    END
  END rw0_rd_out[61]
  PIN rw0_rd_out[62]
    DIRECTION OUTPUT ;
    USE SIGNAL ;
    SHAPE ABUTMENT ;
    PORT
      LAYER M2_m ;
      RECT 6.759 24.530 6.777 24.584 ;
    END
  END rw0_rd_out[62]
  PIN rw0_rd_out[63]
    DIRECTION OUTPUT ;
    USE SIGNAL ;
    SHAPE ABUTMENT ;
    PORT
      LAYER M2_m ;
      RECT 7.227 24.530 7.245 24.584 ;
    END
  END rw0_rd_out[63]
  PIN rw0_rd_out[64]
    DIRECTION OUTPUT ;
    USE SIGNAL ;
    SHAPE ABUTMENT ;
    PORT
      LAYER M2_m ;
      RECT 7.695 24.530 7.713 24.584 ;
    END
  END rw0_rd_out[64]
  PIN rw0_rd_out[65]
    DIRECTION OUTPUT ;
    USE SIGNAL ;
    SHAPE ABUTMENT ;
    PORT
      LAYER M2_m ;
      RECT 8.163 24.530 8.181 24.584 ;
    END
  END rw0_rd_out[65]
  PIN rw0_rd_out[66]
    DIRECTION OUTPUT ;
    USE SIGNAL ;
    SHAPE ABUTMENT ;
    PORT
      LAYER M2_m ;
      RECT 8.631 24.530 8.649 24.584 ;
    END
  END rw0_rd_out[66]
  PIN rw0_rd_out[67]
    DIRECTION OUTPUT ;
    USE SIGNAL ;
    SHAPE ABUTMENT ;
    PORT
      LAYER M2_m ;
      RECT 9.099 24.530 9.117 24.584 ;
    END
  END rw0_rd_out[67]
  PIN rw0_rd_out[68]
    DIRECTION OUTPUT ;
    USE SIGNAL ;
    SHAPE ABUTMENT ;
    PORT
      LAYER M2_m ;
      RECT 9.567 24.530 9.585 24.584 ;
    END
  END rw0_rd_out[68]
  PIN rw0_rd_out[69]
    DIRECTION OUTPUT ;
    USE SIGNAL ;
    SHAPE ABUTMENT ;
    PORT
      LAYER M2_m ;
      RECT 10.035 24.530 10.053 24.584 ;
    END
  END rw0_rd_out[69]
  PIN rw0_rd_out[70]
    DIRECTION OUTPUT ;
    USE SIGNAL ;
    SHAPE ABUTMENT ;
    PORT
      LAYER M2_m ;
      RECT 10.503 24.530 10.521 24.584 ;
    END
  END rw0_rd_out[70]
  PIN rw0_rd_out[71]
    DIRECTION OUTPUT ;
    USE SIGNAL ;
    SHAPE ABUTMENT ;
    PORT
      LAYER M2_m ;
      RECT 10.971 24.530 10.989 24.584 ;
    END
  END rw0_rd_out[71]
  PIN rw0_rd_out[72]
    DIRECTION OUTPUT ;
    USE SIGNAL ;
    SHAPE ABUTMENT ;
    PORT
      LAYER M2_m ;
      RECT 11.439 24.530 11.457 24.584 ;
    END
  END rw0_rd_out[72]
  PIN rw0_rd_out[73]
    DIRECTION OUTPUT ;
    USE SIGNAL ;
    SHAPE ABUTMENT ;
    PORT
      LAYER M2_m ;
      RECT 11.907 24.530 11.925 24.584 ;
    END
  END rw0_rd_out[73]
  PIN rw0_rd_out[74]
    DIRECTION OUTPUT ;
    USE SIGNAL ;
    SHAPE ABUTMENT ;
    PORT
      LAYER M2_m ;
      RECT 12.375 24.530 12.393 24.584 ;
    END
  END rw0_rd_out[74]
  PIN rw0_rd_out[75]
    DIRECTION OUTPUT ;
    USE SIGNAL ;
    SHAPE ABUTMENT ;
    PORT
      LAYER M2_m ;
      RECT 12.843 24.530 12.861 24.584 ;
    END
  END rw0_rd_out[75]
  PIN rw0_rd_out[76]
    DIRECTION OUTPUT ;
    USE SIGNAL ;
    SHAPE ABUTMENT ;
    PORT
      LAYER M2_m ;
      RECT 13.311 24.530 13.329 24.584 ;
    END
  END rw0_rd_out[76]
  PIN rw0_rd_out[77]
    DIRECTION OUTPUT ;
    USE SIGNAL ;
    SHAPE ABUTMENT ;
    PORT
      LAYER M2_m ;
      RECT 13.779 24.530 13.797 24.584 ;
    END
  END rw0_rd_out[77]
  PIN rw0_rd_out[78]
    DIRECTION OUTPUT ;
    USE SIGNAL ;
    SHAPE ABUTMENT ;
    PORT
      LAYER M2_m ;
      RECT 14.247 24.530 14.265 24.584 ;
    END
  END rw0_rd_out[78]
  PIN rw0_rd_out[79]
    DIRECTION OUTPUT ;
    USE SIGNAL ;
    SHAPE ABUTMENT ;
    PORT
      LAYER M2_m ;
      RECT 14.715 24.530 14.733 24.584 ;
    END
  END rw0_rd_out[79]
  PIN rw0_rd_out[80]
    DIRECTION OUTPUT ;
    USE SIGNAL ;
    SHAPE ABUTMENT ;
    PORT
      LAYER M2_m ;
      RECT 15.183 24.530 15.201 24.584 ;
    END
  END rw0_rd_out[80]
  PIN rw0_rd_out[81]
    DIRECTION OUTPUT ;
    USE SIGNAL ;
    SHAPE ABUTMENT ;
    PORT
      LAYER M2_m ;
      RECT 15.651 24.530 15.669 24.584 ;
    END
  END rw0_rd_out[81]
  PIN rw0_rd_out[82]
    DIRECTION OUTPUT ;
    USE SIGNAL ;
    SHAPE ABUTMENT ;
    PORT
      LAYER M2_m ;
      RECT 16.119 24.530 16.137 24.584 ;
    END
  END rw0_rd_out[82]
  PIN rw0_rd_out[83]
    DIRECTION OUTPUT ;
    USE SIGNAL ;
    SHAPE ABUTMENT ;
    PORT
      LAYER M2_m ;
      RECT 16.587 24.530 16.605 24.584 ;
    END
  END rw0_rd_out[83]
  PIN rw0_rd_out[84]
    DIRECTION OUTPUT ;
    USE SIGNAL ;
    SHAPE ABUTMENT ;
    PORT
      LAYER M2_m ;
      RECT 17.055 24.530 17.073 24.584 ;
    END
  END rw0_rd_out[84]
  PIN rw0_rd_out[85]
    DIRECTION OUTPUT ;
    USE SIGNAL ;
    SHAPE ABUTMENT ;
    PORT
      LAYER M2_m ;
      RECT 17.523 24.530 17.541 24.584 ;
    END
  END rw0_rd_out[85]
  PIN rw0_rd_out[86]
    DIRECTION OUTPUT ;
    USE SIGNAL ;
    SHAPE ABUTMENT ;
    PORT
      LAYER M2_m ;
      RECT 17.991 24.530 18.009 24.584 ;
    END
  END rw0_rd_out[86]
  PIN rw0_rd_out[87]
    DIRECTION OUTPUT ;
    USE SIGNAL ;
    SHAPE ABUTMENT ;
    PORT
      LAYER M2_m ;
      RECT 18.459 24.530 18.477 24.584 ;
    END
  END rw0_rd_out[87]
  PIN rw0_rd_out[88]
    DIRECTION OUTPUT ;
    USE SIGNAL ;
    SHAPE ABUTMENT ;
    PORT
      LAYER M2_m ;
      RECT 18.927 24.530 18.945 24.584 ;
    END
  END rw0_rd_out[88]
  PIN rw0_rd_out[89]
    DIRECTION OUTPUT ;
    USE SIGNAL ;
    SHAPE ABUTMENT ;
    PORT
      LAYER M2_m ;
      RECT 19.395 24.530 19.413 24.584 ;
    END
  END rw0_rd_out[89]
  PIN rw0_rd_out[90]
    DIRECTION OUTPUT ;
    USE SIGNAL ;
    SHAPE ABUTMENT ;
    PORT
      LAYER M2_m ;
      RECT 19.863 24.530 19.881 24.584 ;
    END
  END rw0_rd_out[90]
  PIN rw0_rd_out[91]
    DIRECTION OUTPUT ;
    USE SIGNAL ;
    SHAPE ABUTMENT ;
    PORT
      LAYER M2_m ;
      RECT 20.331 24.530 20.349 24.584 ;
    END
  END rw0_rd_out[91]
  PIN rw0_rd_out[92]
    DIRECTION OUTPUT ;
    USE SIGNAL ;
    SHAPE ABUTMENT ;
    PORT
      LAYER M2_m ;
      RECT 20.799 24.530 20.817 24.584 ;
    END
  END rw0_rd_out[92]
  PIN rw0_rd_out[93]
    DIRECTION OUTPUT ;
    USE SIGNAL ;
    SHAPE ABUTMENT ;
    PORT
      LAYER M2_m ;
      RECT 21.267 24.530 21.285 24.584 ;
    END
  END rw0_rd_out[93]
  PIN rw0_rd_out[94]
    DIRECTION OUTPUT ;
    USE SIGNAL ;
    SHAPE ABUTMENT ;
    PORT
      LAYER M2_m ;
      RECT 21.735 24.530 21.753 24.584 ;
    END
  END rw0_rd_out[94]
  PIN rw0_addr_in[0]
    DIRECTION INPUT ;
    USE SIGNAL ;
    SHAPE ABUTMENT ;
    PORT
      LAYER M3_m ;
      RECT 0.000 19.860 0.072 19.884 ;
    END
  END rw0_addr_in[0]
  PIN rw0_addr_in[1]
    DIRECTION INPUT ;
    USE SIGNAL ;
    SHAPE ABUTMENT ;
    PORT
      LAYER M3_m ;
      RECT 0.000 20.676 0.072 20.700 ;
    END
  END rw0_addr_in[1]
  PIN rw0_addr_in[2]
    DIRECTION INPUT ;
    USE SIGNAL ;
    SHAPE ABUTMENT ;
    PORT
      LAYER M3_m ;
      RECT 0.000 21.492 0.072 21.516 ;
    END
  END rw0_addr_in[2]
  PIN rw0_addr_in[3]
    DIRECTION INPUT ;
    USE SIGNAL ;
    SHAPE ABUTMENT ;
    PORT
      LAYER M3_m ;
      RECT 0.000 22.308 0.072 22.332 ;
    END
  END rw0_addr_in[3]
  PIN rw0_addr_in[4]
    DIRECTION INPUT ;
    USE SIGNAL ;
    SHAPE ABUTMENT ;
    PORT
      LAYER M3_m ;
      RECT 24.552 19.860 24.624 19.884 ;
    END
  END rw0_addr_in[4]
  PIN rw0_addr_in[5]
    DIRECTION INPUT ;
    USE SIGNAL ;
    SHAPE ABUTMENT ;
    PORT
      LAYER M3_m ;
      RECT 24.552 20.676 24.624 20.700 ;
    END
  END rw0_addr_in[5]
  PIN rw0_addr_in[6]
    DIRECTION INPUT ;
    USE SIGNAL ;
    SHAPE ABUTMENT ;
    PORT
      LAYER M3_m ;
      RECT 24.552 21.492 24.624 21.516 ;
    END
  END rw0_addr_in[6]
  PIN rw0_addr_in[7]
    DIRECTION INPUT ;
    USE SIGNAL ;
    SHAPE ABUTMENT ;
    PORT
      LAYER M3_m ;
      RECT 24.552 22.308 24.624 22.332 ;
    END
  END rw0_addr_in[7]
  PIN rw0_we_in
    DIRECTION INPUT ;
    USE SIGNAL ;
    SHAPE ABUTMENT ;
    PORT
      LAYER M2_m ;
      RECT 22.203 24.530 22.221 24.584 ;
    END
  END rw0_we_in
  PIN rw0_ce_in
    DIRECTION INPUT ;
    USE SIGNAL ;
    SHAPE ABUTMENT ;
    PORT
      LAYER M2_m ;
      RECT 22.671 24.530 22.689 24.584 ;
    END
  END rw0_ce_in
  PIN rw0_clk
    DIRECTION INPUT ;
    USE SIGNAL ;
    SHAPE ABUTMENT ;
    PORT
      LAYER M2_m ;
      RECT 23.139 24.530 23.157 24.584 ;
    END
  END rw0_clk
  PIN VSS
    DIRECTION INOUT ;
    USE GROUND ;
    PORT
      LAYER M4_m ;
      RECT 0.168 0.288 0.264 24.296 ;
      RECT 0.936 0.288 1.032 24.296 ;
      RECT 1.704 0.288 1.800 24.296 ;
      RECT 2.472 0.288 2.568 24.296 ;
      RECT 3.240 0.288 3.336 24.296 ;
      RECT 4.008 0.288 4.104 24.296 ;
      RECT 4.776 0.288 4.872 24.296 ;
      RECT 5.544 0.288 5.640 24.296 ;
      RECT 6.312 0.288 6.408 24.296 ;
      RECT 7.080 0.288 7.176 24.296 ;
      RECT 7.848 0.288 7.944 24.296 ;
      RECT 8.616 0.288 8.712 24.296 ;
      RECT 9.384 0.288 9.480 24.296 ;
      RECT 10.152 0.288 10.248 24.296 ;
      RECT 10.920 0.288 11.016 24.296 ;
      RECT 11.688 0.288 11.784 24.296 ;
      RECT 12.456 0.288 12.552 24.296 ;
      RECT 13.224 0.288 13.320 24.296 ;
      RECT 13.992 0.288 14.088 24.296 ;
      RECT 14.760 0.288 14.856 24.296 ;
      RECT 15.528 0.288 15.624 24.296 ;
      RECT 16.296 0.288 16.392 24.296 ;
      RECT 17.064 0.288 17.160 24.296 ;
      RECT 17.832 0.288 17.928 24.296 ;
      RECT 18.600 0.288 18.696 24.296 ;
      RECT 19.368 0.288 19.464 24.296 ;
      RECT 20.136 0.288 20.232 24.296 ;
      RECT 20.904 0.288 21.000 24.296 ;
      RECT 21.672 0.288 21.768 24.296 ;
      RECT 22.440 0.288 22.536 24.296 ;
      RECT 23.208 0.288 23.304 24.296 ;
      RECT 23.976 0.288 24.072 24.296 ;
    END
  END VSS
  PIN VDD
    DIRECTION INOUT ;
    USE POWER ;
    PORT
      LAYER M4_m ;
      RECT 0.168 0.288 0.264 24.296 ;
      RECT 0.936 0.288 1.032 24.296 ;
      RECT 1.704 0.288 1.800 24.296 ;
      RECT 2.472 0.288 2.568 24.296 ;
      RECT 3.240 0.288 3.336 24.296 ;
      RECT 4.008 0.288 4.104 24.296 ;
      RECT 4.776 0.288 4.872 24.296 ;
      RECT 5.544 0.288 5.640 24.296 ;
      RECT 6.312 0.288 6.408 24.296 ;
      RECT 7.080 0.288 7.176 24.296 ;
      RECT 7.848 0.288 7.944 24.296 ;
      RECT 8.616 0.288 8.712 24.296 ;
      RECT 9.384 0.288 9.480 24.296 ;
      RECT 10.152 0.288 10.248 24.296 ;
      RECT 10.920 0.288 11.016 24.296 ;
      RECT 11.688 0.288 11.784 24.296 ;
      RECT 12.456 0.288 12.552 24.296 ;
      RECT 13.224 0.288 13.320 24.296 ;
      RECT 13.992 0.288 14.088 24.296 ;
      RECT 14.760 0.288 14.856 24.296 ;
      RECT 15.528 0.288 15.624 24.296 ;
      RECT 16.296 0.288 16.392 24.296 ;
      RECT 17.064 0.288 17.160 24.296 ;
      RECT 17.832 0.288 17.928 24.296 ;
      RECT 18.600 0.288 18.696 24.296 ;
      RECT 19.368 0.288 19.464 24.296 ;
      RECT 20.136 0.288 20.232 24.296 ;
      RECT 20.904 0.288 21.000 24.296 ;
      RECT 21.672 0.288 21.768 24.296 ;
      RECT 22.440 0.288 22.536 24.296 ;
      RECT 23.208 0.288 23.304 24.296 ;
      RECT 23.976 0.288 24.072 24.296 ;
    END
  END VDD
  OBS
    LAYER M1_m ;
    RECT 0 0 24.624 24.584 ;
    LAYER M2_m ;
    RECT 0 0 24.624 24.584 ;
    LAYER M3_m ;
    RECT 0 0 24.624 24.584 ;
    LAYER M4_m ;
    RECT 0 0 24.624 24.584 ;
  END
END ht_asap7_blackparrot_256x95_upper

END LIBRARY
